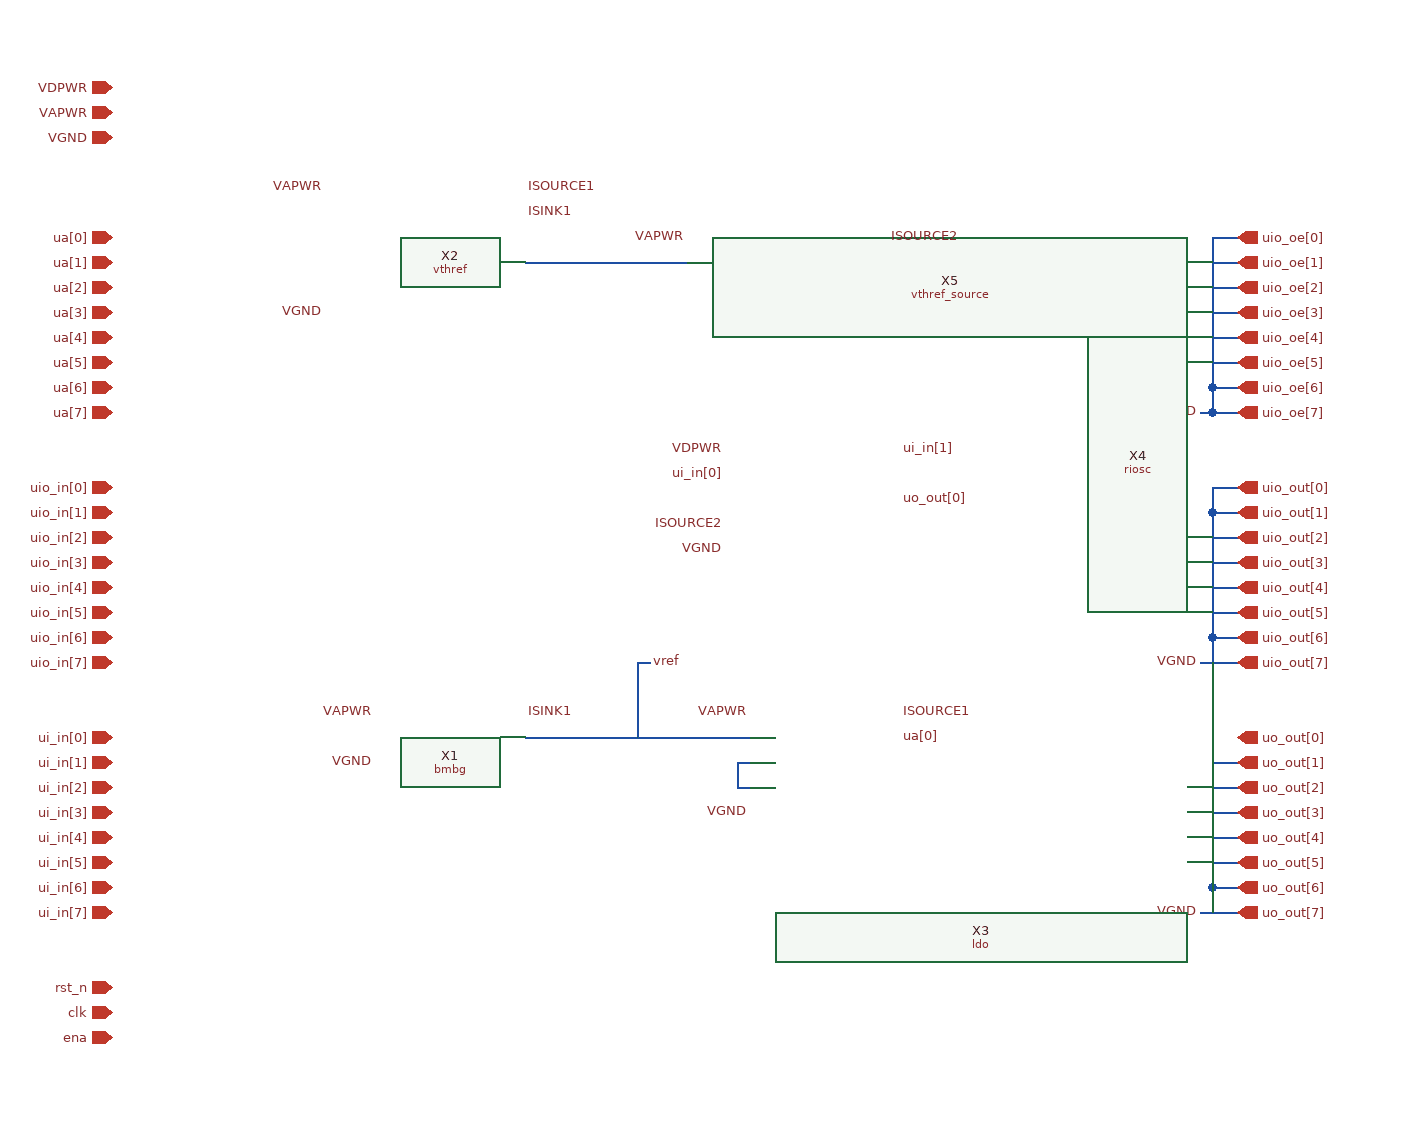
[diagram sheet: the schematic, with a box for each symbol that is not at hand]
v {xschem version=3.4.5 file_version=1.2
}
G {}
K {}
V {}
S {}
E {}
N 960 -740 980 -740 {
lab=uio_oe[0]}
N 960 -740 960 -620 {
lab=uio_oe[0]}
N 960 -640 980 -640 {
lab=uio_oe[0]}
N 960 -660 980 -660 {
lab=uio_oe[0]}
N 960 -680 980 -680 {
lab=uio_oe[0]}
N 960 -700 980 -700 {
lab=uio_oe[0]}
N 960 -720 980 -720 {
lab=uio_oe[0]}
N 960 -440 980 -440 {
lab=uio_out[0]}
N 960 -460 980 -460 {
lab=uio_out[0]}
N 960 -480 980 -480 {
lab=uio_out[0]}
N 960 -500 980 -500 {
lab=uio_out[0]}
N 960 -520 980 -520 {
lab=uio_out[0]}
N 960 -240 980 -240 {
lab=uo_out[1]}
N 960 -260 980 -260 {
lab=uo_out[1]}
N 960 -280 980 -280 {
lab=uo_out[1]}
N 960 -300 980 -300 {
lab=uo_out[1]}
N 960 -320 980 -320 {
lab=uo_out[1]}
N 410 -720 540 -720 {
lab=#net1}
N 410 -340 590 -340 {
lab=vref}
N 500 -400 510 -400 {
lab=vref}
N 500 -400 500 -340 {
lab=vref}
N 580 -300 590 -300 {
lab=#net2}
N 580 -320 580 -300 {
lab=#net2}
N 580 -320 590 -320 {
lab=#net2}
N 960 -520 960 -420 {
lab=uio_out[0]}
N 960 -540 980 -540 {
lab=uio_out[0]}
N 960 -540 960 -520 {
lab=uio_out[0]}
N 960 -320 960 -220 {
lab=uo_out[1]}
N 960 -620 960 -600 {
lab=uio_oe[0]}
N 960 -600 980 -600 {
lab=uio_oe[0]}
N 960 -620 980 -620 {
lab=uio_oe[0]}
N 950 -600 960 -600 {
lab=uio_oe[0]}
N 960 -420 980 -420 {
lab=uio_out[0]}
N 950 -400 980 -400 {
lab=uio_out[0]}
N 960 -420 960 -400 {
lab=uio_out[0]}
N 950 -200 980 -200 {
lab=uo_out[1]}
N 960 -220 960 -200 {
lab=uo_out[1]}
N 960 -220 980 -220 {
lab=uo_out[1]}
C {devices/title.sym} 160 -30 0 0 {name=l1 author="Lukas Baumann"}
C {devices/iopin.sym} 80 -740 2 0 {name=p2 lab=ua[0]

}
C {devices/opin.sym} 980 -740 0 0 {name=p4 lab=uio_oe[0]}
C {devices/iopin.sym} 80 -720 2 0 {name=p3 lab=ua[1]

}
C {devices/iopin.sym} 80 -700 2 0 {name=p5 lab=ua[2]

}
C {devices/iopin.sym} 80 -680 2 0 {name=p9 lab=ua[3]

}
C {devices/iopin.sym} 80 -660 2 0 {name=p10 lab=ua[4]

}
C {devices/iopin.sym} 80 -640 2 0 {name=p11 lab=ua[5]

}
C {devices/iopin.sym} 80 -620 2 0 {name=p12 lab=ua[6]

}
C {devices/opin.sym} 980 -720 0 0 {name=p14 lab=uio_oe[1]}
C {devices/opin.sym} 980 -700 0 0 {name=p15 lab=uio_oe[2]}
C {devices/opin.sym} 980 -680 0 0 {name=p16 lab=uio_oe[3]}
C {devices/opin.sym} 980 -660 0 0 {name=p17 lab=uio_oe[4]}
C {devices/opin.sym} 980 -640 0 0 {name=p18 lab=uio_oe[5]}
C {devices/opin.sym} 980 -620 0 0 {name=p19 lab=uio_oe[6]}
C {devices/opin.sym} 980 -540 0 0 {name=p21 lab=uio_out[0]}
C {devices/opin.sym} 980 -520 0 0 {name=p22 lab=uio_out[1]}
C {devices/opin.sym} 980 -500 0 0 {name=p23 lab=uio_out[2]}
C {devices/opin.sym} 980 -480 0 0 {name=p24 lab=uio_out[3]}
C {devices/opin.sym} 980 -460 0 0 {name=p25 lab=uio_out[4]}
C {devices/opin.sym} 980 -440 0 0 {name=p26 lab=uio_out[5]}
C {devices/opin.sym} 980 -420 0 0 {name=p27 lab=uio_out[6]}
C {devices/ipin.sym} 80 -540 0 0 {name=p13 lab=uio_in[0]}
C {devices/ipin.sym} 80 -520 0 0 {name=p20 lab=uio_in[1]}
C {devices/ipin.sym} 80 -500 0 0 {name=p28 lab=uio_in[2]}
C {devices/ipin.sym} 80 -480 0 0 {name=p29 lab=uio_in[3]}
C {devices/ipin.sym} 80 -460 0 0 {name=p30 lab=uio_in[4]}
C {devices/ipin.sym} 80 -440 0 0 {name=p31 lab=uio_in[5]}
C {devices/ipin.sym} 80 -420 0 0 {name=p32 lab=uio_in[6]}
C {devices/ipin.sym} 80 -340 0 0 {name=p33 lab=ui_in[0]}
C {devices/ipin.sym} 80 -320 0 0 {name=p34 lab=ui_in[1]}
C {devices/ipin.sym} 80 -300 0 0 {name=p35 lab=ui_in[2]}
C {devices/ipin.sym} 80 -280 0 0 {name=p36 lab=ui_in[3]}
C {devices/ipin.sym} 80 -260 0 0 {name=p37 lab=ui_in[4]}
C {devices/ipin.sym} 80 -240 0 0 {name=p38 lab=ui_in[5]}
C {devices/ipin.sym} 80 -220 0 0 {name=p39 lab=ui_in[6]}
C {devices/opin.sym} 980 -340 0 0 {name=p40 lab=uo_out[0]}
C {devices/opin.sym} 980 -320 0 0 {name=p41 lab=uo_out[1]}
C {devices/opin.sym} 980 -300 0 0 {name=p42 lab=uo_out[2]}
C {devices/opin.sym} 980 -280 0 0 {name=p43 lab=uo_out[3]}
C {devices/opin.sym} 980 -260 0 0 {name=p44 lab=uo_out[4]}
C {devices/opin.sym} 980 -240 0 0 {name=p45 lab=uo_out[5]}
C {devices/opin.sym} 980 -220 0 0 {name=p46 lab=uo_out[6]}
C {devices/ipin.sym} 80 -140 0 0 {name=p47 lab=rst_n}
C {devices/ipin.sym} 80 -120 0 0 {name=p1 lab=clk}
C {devices/ipin.sym} 80 -100 0 0 {name=p48 lab=ena}
C {devices/iopin.sym} 80 -860 2 0 {name=p49 lab=VDPWR

}
C {devices/iopin.sym} 80 -840 2 0 {name=p50 lab=VAPWR

}
C {devices/iopin.sym} 80 -820 2 0 {name=p51 lab=VGND

}
C {devices/lab_pin.sym} 950 -600 0 0 {name=p6 sig_type=std_logic lab=VGND}
C {devices/lab_pin.sym} 950 -400 0 0 {name=p7 sig_type=std_logic lab=VGND}
C {devices/lab_pin.sym} 950 -200 0 0 {name=p8 sig_type=std_logic lab=VGND}
C {bmbg.sym} 350 -340 0 0 {name=X1}
C {vthref.sym} 330 -760 0 0 {name=X2}
C {ldo.sym} 650 -340 0 0 {name=X3}
C {riosc.sym} 640 -530 0 0 {name=X4}
C {vthref_source.sym} 620 -730 0 0 {name=X5}
C {devices/lab_pin.sym} 290 -320 0 0 {name=p52 sig_type=std_logic lab=VGND}
C {devices/lab_pin.sym} 250 -680 0 0 {name=p53 sig_type=std_logic lab=VGND}
C {devices/lab_pin.sym} 570 -490 0 0 {name=p54 sig_type=std_logic lab=VGND}
C {devices/lab_pin.sym} 590 -280 0 0 {name=p55 sig_type=std_logic lab=VGND}
C {devices/lab_pin.sym} 250 -780 0 0 {name=p56 sig_type=std_logic lab=VAPWR}
C {devices/lab_pin.sym} 540 -740 0 0 {name=p57 sig_type=std_logic lab=VAPWR}
C {devices/lab_pin.sym} 410 -780 0 1 {name=p58 sig_type=std_logic lab=ISOURCE1}
C {devices/lab_pin.sym} 410 -760 0 1 {name=p59 sig_type=std_logic lab=ISINK1}
C {devices/lab_pin.sym} 700 -740 0 1 {name=p60 sig_type=std_logic lab=ISOURCE2}
C {devices/lab_pin.sym} 290 -360 0 0 {name=p61 sig_type=std_logic lab=VAPWR}
C {devices/lab_pin.sym} 570 -570 0 0 {name=p62 sig_type=std_logic lab=VDPWR}
C {devices/lab_pin.sym} 710 -340 0 1 {name=p63 sig_type=std_logic lab=ua[0]}
C {devices/lab_pin.sym} 710 -360 0 1 {name=p64 sig_type=std_logic lab=ISOURCE1}
C {devices/lab_pin.sym} 590 -360 0 0 {name=p65 sig_type=std_logic lab=VAPWR}
C {devices/lab_pin.sym} 410 -360 0 1 {name=p66 sig_type=std_logic lab=ISINK1}
C {devices/lab_pin.sym} 510 -400 0 1 {name=p67 sig_type=std_logic lab=vref}
C {devices/lab_pin.sym} 570 -510 0 0 {name=p68 sig_type=std_logic lab=ISOURCE2}
C {devices/lab_pin.sym} 570 -550 0 0 {name=p69 sig_type=std_logic lab=ui_in[0]}
C {devices/lab_pin.sym} 710 -570 0 1 {name=p70 sig_type=std_logic lab=ui_in[1]}
C {devices/lab_pin.sym} 710 -530 0 1 {name=p71 sig_type=std_logic lab=uo_out[0]}
C {devices/iopin.sym} 80 -600 2 0 {name=p72 lab=ua[7]

}
C {devices/ipin.sym} 80 -400 0 0 {name=p73 lab=uio_in[7]}
C {devices/ipin.sym} 80 -200 0 0 {name=p74 lab=ui_in[7]}
C {devices/opin.sym} 980 -600 0 0 {name=p75 lab=uio_oe[7]}
C {devices/opin.sym} 980 -400 0 0 {name=p76 lab=uio_out[7]}
C {devices/opin.sym} 980 -200 0 0 {name=p77 lab=uo_out[7]}
